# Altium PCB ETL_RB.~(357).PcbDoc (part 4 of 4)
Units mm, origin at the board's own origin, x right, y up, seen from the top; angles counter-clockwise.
Board outline 130.3 x 56.5 mm, 8 copper layers (Top Layer, plane 1, M1, plane 2, plane 3, M2, plane 4, Bottom Layer), stack 0.972 mm thick; 211 components, 188 nets, 1864 pads, 1049 vias.
Unrouted connection lines stored in the file: 383.

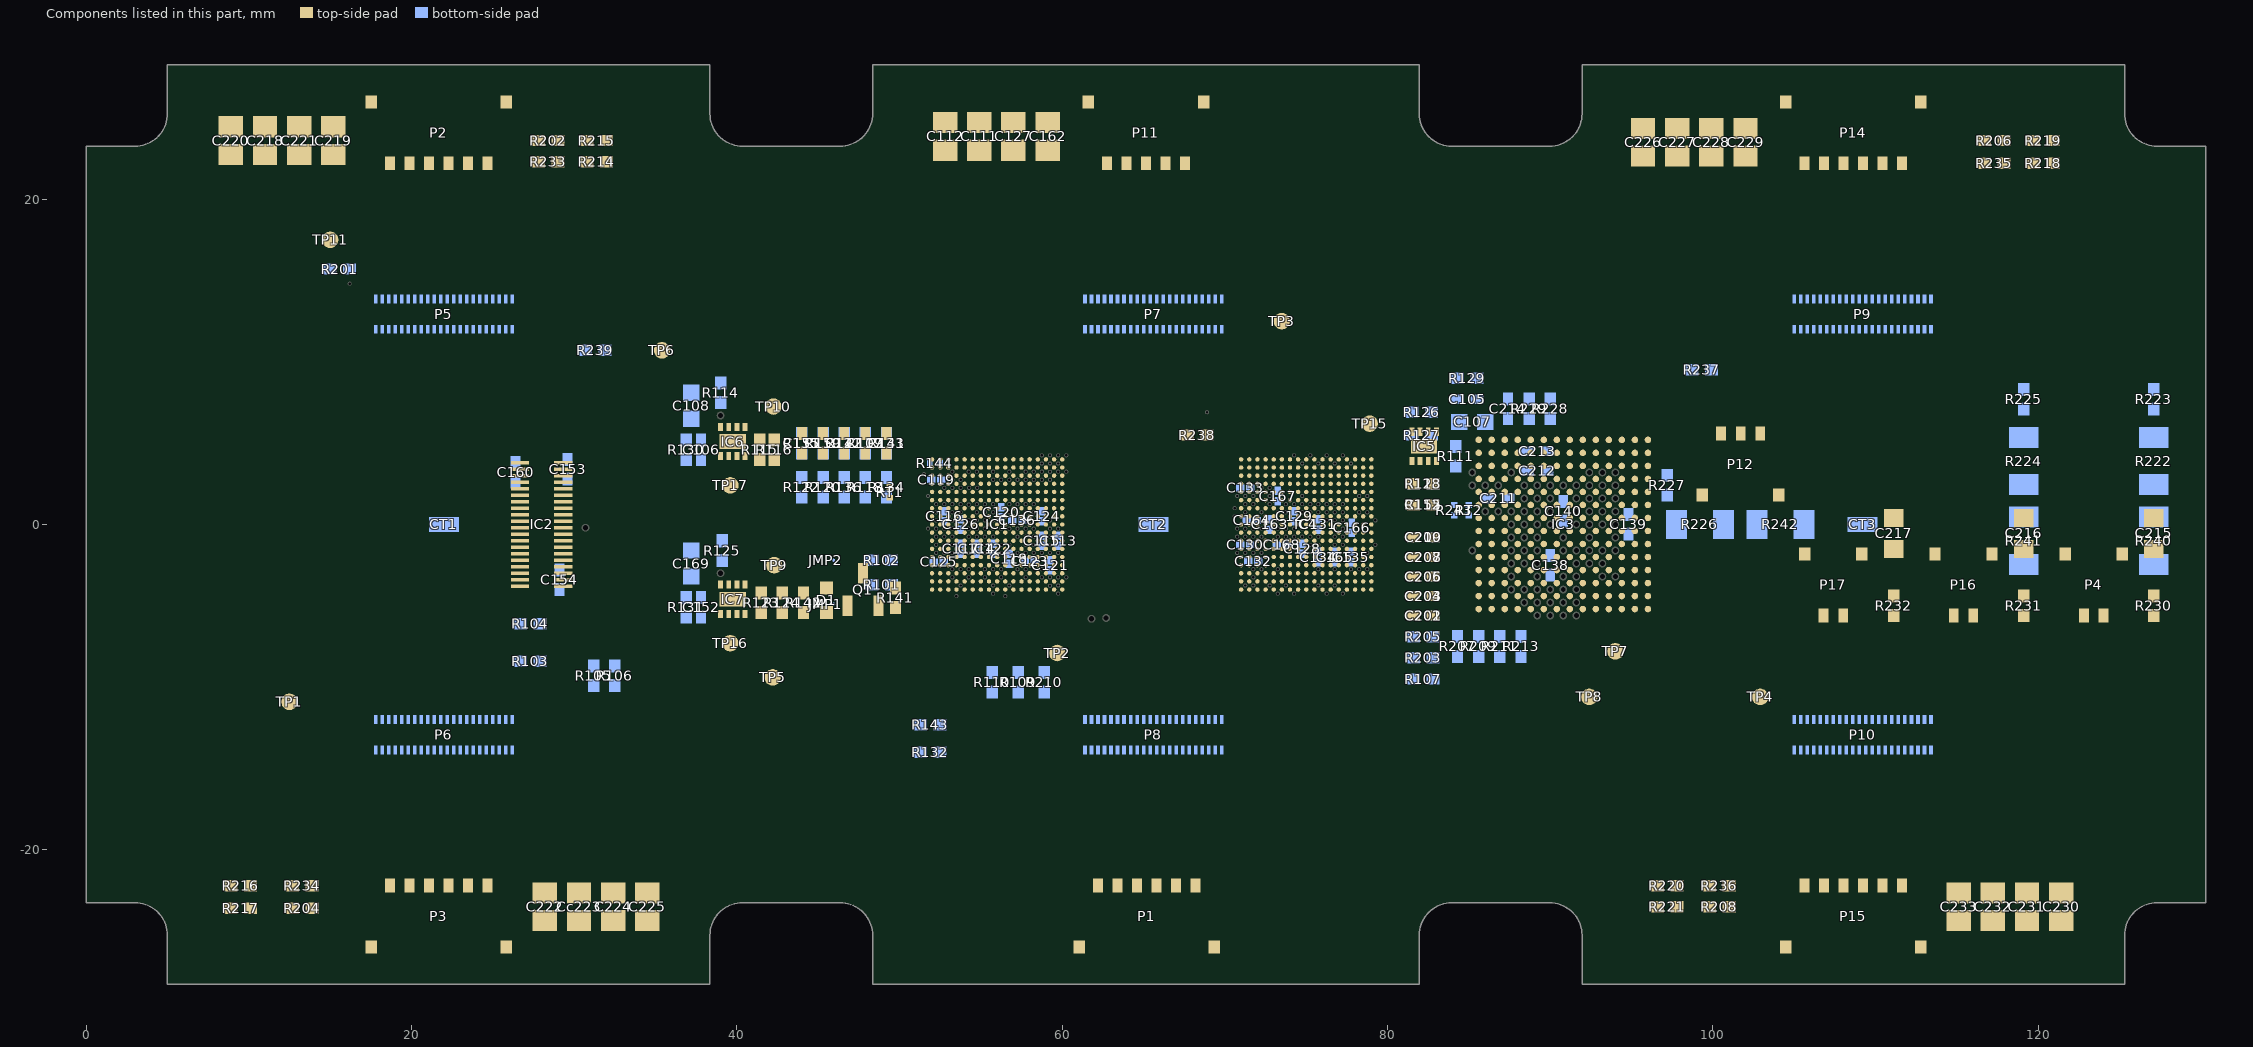
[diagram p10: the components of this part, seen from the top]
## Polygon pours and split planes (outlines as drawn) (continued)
1V2_RB on plane 2 (split plane): 65.195,-4.305 65.22,-4.322 65.25,-4.328 71.75,-4.328 71.78,-4.322 71.805,-4.305 72.782,-3.328 85.5,-3.328 85.53,-3.322 85.555,-3.305 86.032,-2.828 91.968,-2.828 101.945,-12.805 101.97,-12.822 102,-12.828 107.218,-12.828 109.672,-15.282 109.672,-22.172 101.282,-22.172 95.005,-15.895 94.98,-15.878 94.95,-15.872 94.929,-15.876 94.908,-15.872 78.432,-15.872 75.455,-12.895 75.43,-12.878 75.4,-12.872 66.55,-12.872 66.52,-12.878 66.495,-12.895 65.545,-13.845 65.528,-13.87 65.522,-13.9 65.522,-15.268 64.868,-15.922 17.282,-15.922 16.828,-15.468 16.828,-9.532 17.282,-9.078 42,-9.078 42.03,-9.072 42.055,-9.055 47.782,-3.328 51.25,-3.328 51.28,-3.322 51.305,-3.305 52.282,-2.328 63.218,-2.328
1V2_RB on plane 2 (split plane): 271 vertices, not listed, extent 0.51,-27.74 129.79,27.74

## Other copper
Top Layer:
  rectangle net GND: 14.4,-26.4 35.3,-24.4
  rectangle net 1V2B: 23.2,-22.6 35.3,-18.8
  rectangle net GND: 8.1,24.6 27.1,26.4
  rectangle net 1V2A: 8.1,19.8 20.2,22.6
  rectangle net GND: 94.9,24.7 114.4,26.4
  rectangle net 1V2C: 94.9,18.7 107.2,22.7
  rectangle net 1V2D: 110.1,-22.6 122.1,-19.1
  rectangle net GND: 113.8,-26.4 122.2,-23.7
  rectangle net GND: 97.6,1.4 99.7,3.3
  rectangle net BV2: 108.8,-2.8 111.7,-0.9
  rectangle: 113.3,-2.8 114.4,-0.9
  rectangle: 121.3,-2.9 122.5,-0.9
  rectangle net BV1: 116.8,-2.9 119.7,-0.9
  rectangle net BV0: 124.8,-2.9 127.7,-0.9
  rectangle: 103.7,-2.8 106,-0.9
  rectangle: 103.7,1.4 105.8,3.3
  rectangle net LV_RB: 67.25,21.75 70.5,22.6
  rectangle net GND: 58,-22.7 62.5,-18.9
  rectangle net GND: 37.95,-5.1 38.65,-3.9
  rectangle net GND: 38.6,-5.1 39.05,-4.15
  rectangle net GND: 38.1,4.6 39,5.6
  rectangle net GND: 16.3,-21.1 22.6,-17.8
  rectangle net GND: 20.8,-22.6 22.6,-20.6
  rectangle net GND: 101.7,-26.4 115.5,-24.5
  rectangle net GND: 103.1,-21.1 109.6,-18.4
  rectangle net GND: 107.7,-22.6 109.6,-21.1
  rectangle net GND: 107.7,17.9 114.5,21.2
  rectangle net GND: 107.7,21 109.5,22.6
  rectangle net GND: 58,-26.4 72.4,-24.5
  rectangle net GND: 80.2,4.35 81.6,5.25
  rectangle net GND: 22.4,18.8 26.6,20.6
  rectangle net GND: 20.8,18.8 22.6,22.6
  rectangle net GND: 66.4,18.5 70.5,21.2
  rectangle net GND: 64.9,18.5 66.6,22.6
  rectangle net GND: 52,24.2 70.4,26.5
  rectangle net 1V2_RB: 52,20.2 64.3,22.6
Bottom Layer:
  rectangle net GND: 58.7,12.425 70.1,13.425
  rectangle net GND: 26.1,2.1 27.9,3.1
  rectangle net GND: 28.2,2.4 29.9,3.3
  rectangle net GND: 28.1,-3.3 29.4,-2.4
  rectangle net GND: 37.5,-5.1 38.7,-3.9
  rectangle net GND: 37.5,4.6 38.7,5.6
  rectangle net GND: 14.8,9.3 17.9,12.7
  rectangle net GND: 58.7,9.3 61.4,12.6
  rectangle net GND: 63.7,9.3 65.5,12.6
  rectangle net GND: 107.3,9.3 109.1,12.6
  rectangle net GND: 101.7,9.3 105.1,13.425
  rectangle net GND: 101.7,12.425 113.7,13.425
  rectangle net GND: 20.1,9.3 21.9,12.6
  rectangle net GND: 22.1,-12.6 23.9,-11.4
  rectangle net GND: 22.1,-11.5 24.7,-9.3
  rectangle net GND: 110.1,-12.6 111.1,-11.4
  rectangle net GND: 110.1,-11.5 111.9,-9.3
  rectangle net GND: 113.3,-12.7 116.7,-9.3
  rectangle net GND: 67.4,-11.5 68.3,-9.3
  rectangle net GND: 66.1,-12.6 67.5,-9.3
  rectangle net GND: 69.7,-12.7 73.1,-9.3
  rectangle net GND: 26.1,-12.7 29.5,-9.3
  region net GND: 29.5,-12.425 17.5,-12.425 17.5,-13.425 29.5,-13.425
  region net GND: 73.1,-12.425 61.1,-12.425 61.1,-13.425 73.1,-13.425
  region net GND: 116.7,-12.425 104.7,-12.425 104.7,-13.425 116.7,-13.425
  rectangle net GND: 14.8,12.4 26.3,13.4
  rectangle net LV_RB: 35.9,-5.1 37.2,-3.9
  rectangle net I_2V5RX: 36.5,-6.4 39.3,-5.3
  rectangle net I_2V5TX: 36.5,3.3 39.3,4.4
  rectangle net LV_RB: 35.7,4.6 37.3,5.8
  rectangle net 1V2_RB: 25.3,3.4 26.3,4.2
  rectangle net 2V5TX: 29.85,3.6 30.65,4.4
  rectangle net 2V5RX: 28.1,-4.4 28.9,-3.6
  rectangle net 1V2C: 67.7,9.275 69.5,12.275
  rectangle net 1V2C: 65.7,9.275 67.5,12.275
  rectangle net 1V2D: 109.3,9.275 111.1,12.275
  rectangle net 1V2C: 111.3,9.275 113.1,12.275
  region net 1V2D: 109.1,-9.275 107.3,-9.275 107.3,-12.275 109.1,-12.275
  region net 1V2D: 107.1,-9.275 105.3,-9.275 105.3,-12.275 107.1,-12.275
  region net 1V2B: 65.5,-9.275 63.7,-9.275 63.7,-12.275 65.5,-12.275
  region net 1V2B: 63.5,-9.275 61.7,-9.275 61.7,-12.275 63.5,-12.275
  region net 1V2B: 19.9,-9.275 18.1,-9.275 18.1,-12.275 19.9,-12.275
  region net 1V2A: 21.9,-9.275 20.1,-9.275 20.1,-12.275 21.9,-12.275
  rectangle net 1V2A: 22.1,9.275 23.9,12.275
  rectangle net 1V2A: 24.1,9.275 25.9,12.275
plane 2 (plane layer: these items are gaps in the copper):
  lines w0.152: 94.908,-15.95 78.4,-15.95 75.4,-12.95 66.55,-12.95 65.6,-13.9 65.6,-15.3 ; 94.95,-15.95 101.25,-22.25 109.75,-22.25 109.75,-15.25 107.25,-12.75 102,-12.75 92,-2.75 86,-2.75 85.5,-3.25 72.75,-3.25 71.75,-4.25 65.25,-4.25 63.25,-2.25 52.25,-2.25 51.25,-3.25 47.75,-3.25 42,-9 17.25,-9 16.75,-9.5 16.75,-15.5 17.25,-16 64.9,-16 ; 64.9,-16 65.6,-15.3 ; 64.9,-16 65.6,-15.3 ; 18.75,8.05 18.75,11.4 22.1,14.75 22.1,15.7 23.7,17.3 112.65,17.3 114.05,15.9 114.05,9.25 112.85,8.05 102.5,8.05 98.85,11.7 82.05,11.7 76.7,6.35 64.1,6.35 60,2.25 55.5,2.25 55,2.75 54.25,2.75 45.2,11.8 31.3,11.8 27.55,8.05 18.75,8.05
plane 3 (plane layer: these items are gaps in the copper):
  lines w0.152: 0,-8 20,-8 20,-11.5 ; 28.5,28.2 28.5,28.3 ; 29,28.2 29,28.3 29,17 18.5,17 18.5,12 29,12 29,6 25,6 25,-11.5 20,-11.5 ; 70.8,28.3 70.8,14.1 69.2,12.5 ; 75,-28 75,-8.5 60.5,-8.5 60.5,-10.5 62.1,-12.1 68.8,-12.1 68.8,-16.5 17.5,-16.5 17.5,-14 20,-11.5 ; 95.1,-28.3 95.1,-15.8 112.5,-15.8 112.5,-11.5 101.7,-11.5 101.7,11.6 111.2,11.6 ; 130.3,7 130.3,7.1 130.2,7 111.2,7 111.2,11.6 ; 69.2,12.5 69.2,12.5 ; 69.2,12.5 66.3,12.5 65.6,11.8 65.6,8.7 74.1,8.7 81.5,16.1 114,16.1 114,13.1 112.5,11.6 111.2,11.6 ; 79.9,-2.8 85.6,-8.5 95.5,-8.5 95.5,10 83,10 79.9,6.9 79.9,-2.8 ; 82.5,4.1 83.8,2.8 89.6,2.8 89.6,-4.4 92,-4.4 92,5.6 82.5,5.6 82.5,4.1

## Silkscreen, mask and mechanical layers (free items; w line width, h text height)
Top Overlay:
  text "09_03_2020" at 8.892,-6.946 h1.52 r90
  text "ETL_RB_v1.0" at 5.561,-10.2 h2.03 r90
Bottom Overlay:
  text "ETL_RB_v1.0" at 5.061,10.1 h2.03 r90
  text "09_03_2020" at 8.292,6.946 h1.52 r90
Mechanical 1:
  the board outline again, w0.15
